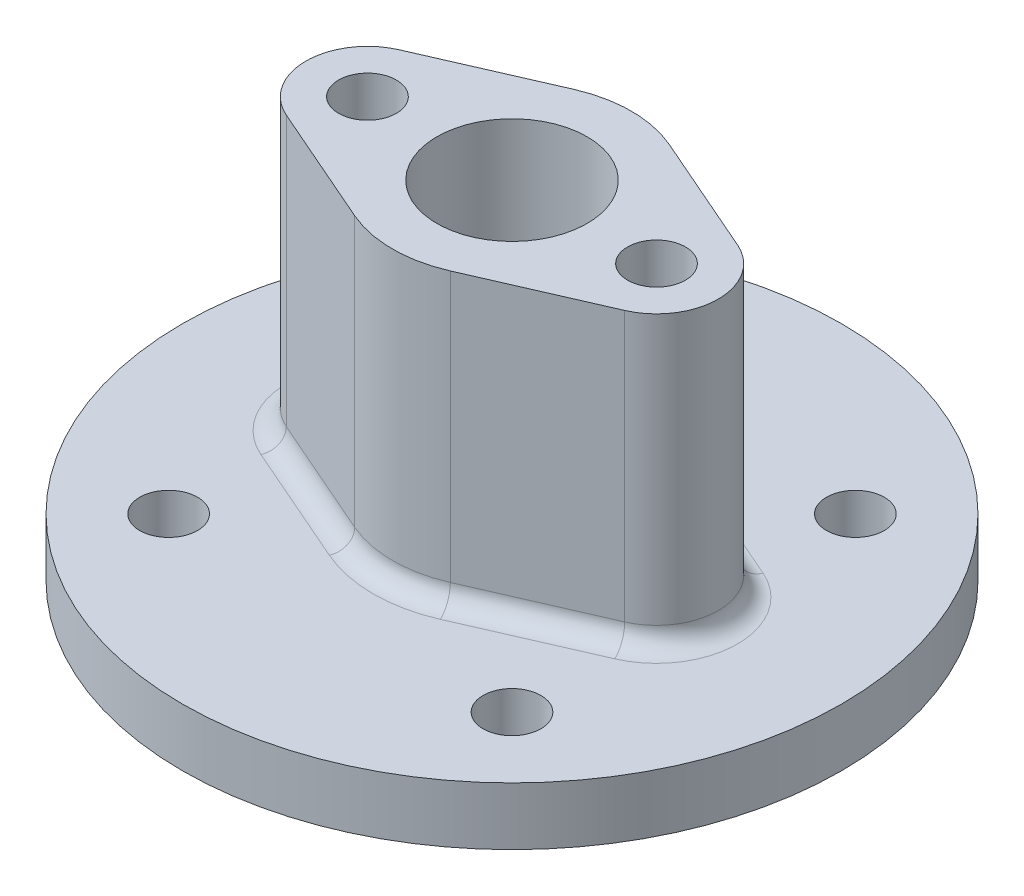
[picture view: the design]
ISO-10303-21;
HEADER;
FILE_DESCRIPTION(('STEP AP214'),'2;1');
FILE_NAME('part.step','',(''),(''),'','','');
FILE_SCHEMA(('AUTOMOTIVE_DESIGN { 1 0 10303 214 1 1 1 1 }'));
ENDSEC;
DATA;
#1=APPLICATION_CONTEXT('core data for automotive mechanical design processes');
#2=APPLICATION_PROTOCOL_DEFINITION('international standard','automotive_design',2000,#1);
#3=PRODUCT_CONTEXT('',#1,'mechanical');
#4=PRODUCT('Part','Part','',(#3));
#5=PRODUCT_RELATED_PRODUCT_CATEGORY('part','',(#4));
#6=PRODUCT_DEFINITION_FORMATION('','',#4);
#7=PRODUCT_DEFINITION_CONTEXT('part definition',#1,'design');
#8=PRODUCT_DEFINITION('design','',#6,#7);
#9=PRODUCT_DEFINITION_SHAPE('','',#8);
#10=(LENGTH_UNIT() NAMED_UNIT(*) SI_UNIT(.MILLI.,.METRE.));
#11=(NAMED_UNIT(*) PLANE_ANGLE_UNIT() SI_UNIT($,.RADIAN.));
#12=(NAMED_UNIT(*) SI_UNIT($,.STERADIAN.) SOLID_ANGLE_UNIT());
#13=UNCERTAINTY_MEASURE_WITH_UNIT(LENGTH_MEASURE(1.E-05),#10,'distance_accuracy_value','');
#14=(GEOMETRIC_REPRESENTATION_CONTEXT(3) GLOBAL_UNCERTAINTY_ASSIGNED_CONTEXT((#13)) GLOBAL_UNIT_ASSIGNED_CONTEXT((#10,
#11,#12)) REPRESENTATION_CONTEXT('',''));
#15=CARTESIAN_POINT('',(0.,0.,0.));
#16=DIRECTION('',(0.,0.,1.));
#17=DIRECTION('',(1.,0.,0.));
#18=AXIS2_PLACEMENT_3D('',#15,#16,#17);
#19=CARTESIAN_POINT('',(0.,0.,0.));
#20=DIRECTION('',(0.,-1.,0.));
#21=DIRECTION('',(0.,0.,-1.));
#22=AXIS2_PLACEMENT_3D('',#19,#20,#21);
#23=PLANE('',#22);
#24=CARTESIAN_POINT('',(0.,0.,0.));
#25=DIRECTION('',(0.,-1.,0.));
#26=DIRECTION('',(0.,0.,-1.));
#27=AXIS2_PLACEMENT_3D('',#24,#25,#26);
#28=CIRCLE('',#27,13.5);
#29=CARTESIAN_POINT('',(0.,0.,-13.5));
#30=VERTEX_POINT('',#29);
#31=EDGE_CURVE('E150',#30,#30,#28,.T.);
#32=ORIENTED_EDGE('',*,*,#31,.F.);
#33=EDGE_LOOP('',(#32));
#34=FACE_BOUND('',#33,.T.);
#35=CARTESIAN_POINT('',(0.,0.,0.));
#36=DIRECTION('',(0.,-1.,0.));
#37=DIRECTION('',(0.,0.,-1.));
#38=AXIS2_PLACEMENT_3D('',#35,#36,#37);
#39=CIRCLE('',#38,24.);
#40=CARTESIAN_POINT('',(0.,0.,-24.));
#41=VERTEX_POINT('',#40);
#42=EDGE_CURVE('E212',#41,#41,#39,.T.);
#43=ORIENTED_EDGE('',*,*,#42,.T.);
#44=EDGE_LOOP('',(#43));
#45=FACE_BOUND('',#44,.T.);
#46=ADVANCED_FACE('F32',(#34,#45),#23,.T.);
#47=CARTESIAN_POINT('',(0.,57.,0.));
#48=DIRECTION('',(0.,1.,0.));
#49=DIRECTION('',(0.,0.,1.));
#50=AXIS2_PLACEMENT_3D('',#47,#48,#49);
#51=PLANE('',#50);
#52=CARTESIAN_POINT('',(0.,57.,0.));
#53=DIRECTION('',(0.,1.,0.));
#54=DIRECTION('',(0.,0.,1.));
#55=AXIS2_PLACEMENT_3D('',#52,#53,#54);
#56=CIRCLE('',#55,36.);
#57=CARTESIAN_POINT('',(14.4,57.,32.994545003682));
#58=VERTEX_POINT('',#57);
#59=CARTESIAN_POINT('',(-14.4,57.,32.994545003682));
#60=VERTEX_POINT('',#59);
#61=EDGE_CURVE('E240',#58,#60,#56,.F.);
#62=ORIENTED_EDGE('',*,*,#61,.T.);
#63=DIRECTION('',(0.916515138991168,0.,0.4));
#64=VECTOR('',#63,1.);
#65=CARTESIAN_POINT('',(-14.4,57.,32.9945450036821));
#66=LINE('',#65,#64);
#67=CARTESIAN_POINT('',(-45.9,57.,19.2468179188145));
#68=VERTEX_POINT('',#67);
#69=EDGE_CURVE('E254',#60,#68,#66,.F.);
#70=ORIENTED_EDGE('',*,*,#69,.T.);
#71=CARTESIAN_POINT('',(-37.5,57.,0.));
#72=DIRECTION('',(0.,1.,0.));
#73=DIRECTION('',(0.,0.,1.));
#74=AXIS2_PLACEMENT_3D('',#71,#72,#73);
#75=CIRCLE('',#74,21.);
#76=CARTESIAN_POINT('',(-45.9,57.,-19.2468179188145));
#77=VERTEX_POINT('',#76);
#78=EDGE_CURVE('E252',#68,#77,#75,.F.);
#79=ORIENTED_EDGE('',*,*,#78,.T.);
#80=DIRECTION('',(-0.916515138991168,0.,0.4));
#81=VECTOR('',#80,1.);
#82=CARTESIAN_POINT('',(-14.4,57.,-32.9945450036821));
#83=LINE('',#82,#81);
#84=CARTESIAN_POINT('',(-14.4,57.,-32.994545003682));
#85=VERTEX_POINT('',#84);
#86=EDGE_CURVE('E250',#77,#85,#83,.F.);
#87=ORIENTED_EDGE('',*,*,#86,.T.);
#88=CARTESIAN_POINT('',(0.,57.,0.));
#89=DIRECTION('',(0.,1.,0.));
#90=DIRECTION('',(0.,0.,1.));
#91=AXIS2_PLACEMENT_3D('',#88,#89,#90);
#92=CIRCLE('',#91,36.);
#93=CARTESIAN_POINT('',(14.4,57.,-32.9945450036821));
#94=VERTEX_POINT('',#93);
#95=EDGE_CURVE('E248',#85,#94,#92,.F.);
#96=ORIENTED_EDGE('',*,*,#95,.T.);
#97=DIRECTION('',(-0.916515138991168,0.,-0.4));
#98=VECTOR('',#97,1.);
#99=CARTESIAN_POINT('',(14.4,57.,-32.9945450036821));
#100=LINE('',#99,#98);
#101=CARTESIAN_POINT('',(45.9,57.,-19.2468179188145));
#102=VERTEX_POINT('',#101);
#103=EDGE_CURVE('E246',#94,#102,#100,.F.);
#104=ORIENTED_EDGE('',*,*,#103,.T.);
#105=CARTESIAN_POINT('',(37.5,57.,0.));
#106=DIRECTION('',(0.,1.,0.));
#107=DIRECTION('',(0.,0.,1.));
#108=AXIS2_PLACEMENT_3D('',#105,#106,#107);
#109=CIRCLE('',#108,21.);
#110=CARTESIAN_POINT('',(45.9,57.,19.2468179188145));
#111=VERTEX_POINT('',#110);
#112=EDGE_CURVE('E244',#102,#111,#109,.F.);
#113=ORIENTED_EDGE('',*,*,#112,.T.);
#114=DIRECTION('',(0.916515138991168,0.,-0.4));
#115=VECTOR('',#114,1.);
#116=CARTESIAN_POINT('',(14.4,57.,32.994545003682));
#117=LINE('',#116,#115);
#118=EDGE_CURVE('E242',#111,#58,#117,.F.);
#119=ORIENTED_EDGE('',*,*,#118,.T.);
#120=EDGE_LOOP('',(#62,#70,#79,#87,#96,#104,#113,#119));
#121=FACE_BOUND('',#120,.T.);
#122=CARTESIAN_POINT('',(44.5477272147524,57.,44.5477272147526));
#123=DIRECTION('',(0.,1.,0.));
#124=DIRECTION('',(-1.,0.,0.));
#125=AXIS2_PLACEMENT_3D('',#122,#123,#124);
#126=CIRCLE('',#125,7.5);
#127=CARTESIAN_POINT('',(44.5477272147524,57.,52.0477272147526));
#128=VERTEX_POINT('',#127);
#129=EDGE_CURVE('E232',#128,#128,#126,.T.);
#130=ORIENTED_EDGE('',*,*,#129,.F.);
#131=EDGE_LOOP('',(#130));
#132=FACE_BOUND('',#131,.T.);
#133=CARTESIAN_POINT('',(-44.5477272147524,57.,44.5477272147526));
#134=DIRECTION('',(0.,1.,0.));
#135=DIRECTION('',(0.,0.,-1.));
#136=AXIS2_PLACEMENT_3D('',#133,#134,#135);
#137=CIRCLE('',#136,7.5);
#138=CARTESIAN_POINT('',(-44.5477272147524,57.,52.0477272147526));
#139=VERTEX_POINT('',#138);
#140=EDGE_CURVE('E296',#139,#139,#137,.T.);
#141=ORIENTED_EDGE('',*,*,#140,.F.);
#142=EDGE_LOOP('',(#141));
#143=FACE_BOUND('',#142,.T.);
#144=CARTESIAN_POINT('',(-44.5477272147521,57.,-44.5477272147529));
#145=DIRECTION('',(0.,1.,0.));
#146=DIRECTION('',(1.,0.,0.));
#147=AXIS2_PLACEMENT_3D('',#144,#145,#146);
#148=CIRCLE('',#147,7.5);
#149=CARTESIAN_POINT('',(-44.5477272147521,57.,-37.0477272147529));
#150=VERTEX_POINT('',#149);
#151=EDGE_CURVE('E290',#150,#150,#148,.T.);
#152=ORIENTED_EDGE('',*,*,#151,.F.);
#153=EDGE_LOOP('',(#152));
#154=FACE_BOUND('',#153,.T.);
#155=CARTESIAN_POINT('',(44.5477272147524,57.,-44.5477272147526));
#156=DIRECTION('',(0.,1.,0.));
#157=DIRECTION('',(0.,0.,1.));
#158=AXIS2_PLACEMENT_3D('',#155,#156,#157);
#159=CIRCLE('',#158,7.5);
#160=CARTESIAN_POINT('',(44.5477272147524,57.,-37.0477272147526));
#161=VERTEX_POINT('',#160);
#162=EDGE_CURVE('E227',#161,#161,#159,.T.);
#163=ORIENTED_EDGE('',*,*,#162,.F.);
#164=EDGE_LOOP('',(#163));
#165=FACE_BOUND('',#164,.T.);
#166=CARTESIAN_POINT('',(0.,57.,0.));
#167=DIRECTION('',(0.,-1.,0.));
#168=DIRECTION('',(0.,0.,-1.));
#169=AXIS2_PLACEMENT_3D('',#166,#167,#168);
#170=CIRCLE('',#169,85.5);
#171=CARTESIAN_POINT('',(0.,57.,-85.5));
#172=VERTEX_POINT('',#171);
#173=EDGE_CURVE('E221',#172,#172,#170,.T.);
#174=ORIENTED_EDGE('',*,*,#173,.F.);
#175=EDGE_LOOP('',(#174));
#176=FACE_BOUND('',#175,.T.);
#177=ADVANCED_FACE('F308',(#121,#132,#143,#154,#165,#176),#51,.T.);
#178=CARTESIAN_POINT('',(0.,0.,0.));
#179=DIRECTION('',(0.,-1.,0.));
#180=DIRECTION('',(0.,0.,-1.));
#181=AXIS2_PLACEMENT_3D('',#178,#179,#180);
#182=CYLINDRICAL_SURFACE('',#181,85.5);
#183=ORIENTED_EDGE('',*,*,#173,.T.);
#184=EDGE_LOOP('',(#183));
#185=FACE_BOUND('',#184,.T.);
#186=CARTESIAN_POINT('',(0.,42.,0.));
#187=DIRECTION('',(0.,-1.,0.));
#188=DIRECTION('',(0.,0.,-1.));
#189=AXIS2_PLACEMENT_3D('',#186,#187,#188);
#190=CIRCLE('',#189,85.5);
#191=CARTESIAN_POINT('',(0.,42.,-85.5));
#192=VERTEX_POINT('',#191);
#193=EDGE_CURVE('E218',#192,#192,#190,.T.);
#194=ORIENTED_EDGE('',*,*,#193,.F.);
#195=EDGE_LOOP('',(#194));
#196=FACE_BOUND('',#195,.T.);
#197=ADVANCED_FACE('F311',(#185,#196),#182,.T.);
#198=CARTESIAN_POINT('',(42.,42.,0.));
#199=DIRECTION('',(0.,-1.,0.));
#200=DIRECTION('',(0.,0.,-1.));
#201=AXIS2_PLACEMENT_3D('',#198,#199,#200);
#202=PLANE('',#201);
#203=CARTESIAN_POINT('',(44.5477272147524,42.,44.5477272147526));
#204=DIRECTION('',(0.,-1.,0.));
#205=DIRECTION('',(0.,0.,-1.));
#206=AXIS2_PLACEMENT_3D('',#203,#204,#205);
#207=CIRCLE('',#206,7.5);
#208=CARTESIAN_POINT('',(44.5477272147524,42.,52.0477272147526));
#209=VERTEX_POINT('',#208);
#210=EDGE_CURVE('E235',#209,#209,#207,.T.);
#211=ORIENTED_EDGE('',*,*,#210,.F.);
#212=EDGE_LOOP('',(#211));
#213=FACE_BOUND('',#212,.T.);
#214=CARTESIAN_POINT('',(-44.5477272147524,42.,44.5477272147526));
#215=DIRECTION('',(0.,-1.,0.));
#216=DIRECTION('',(0.,0.,-1.));
#217=AXIS2_PLACEMENT_3D('',#214,#215,#216);
#218=CIRCLE('',#217,7.5);
#219=CARTESIAN_POINT('',(-44.5477272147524,42.,52.0477272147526));
#220=VERTEX_POINT('',#219);
#221=EDGE_CURVE('E231',#220,#220,#218,.T.);
#222=ORIENTED_EDGE('',*,*,#221,.F.);
#223=EDGE_LOOP('',(#222));
#224=FACE_BOUND('',#223,.T.);
#225=CARTESIAN_POINT('',(-44.5477272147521,42.,-44.5477272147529));
#226=DIRECTION('',(0.,-1.,0.));
#227=DIRECTION('',(0.,0.,-1.));
#228=AXIS2_PLACEMENT_3D('',#225,#226,#227);
#229=CIRCLE('',#228,7.5);
#230=CARTESIAN_POINT('',(-44.5477272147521,42.,-37.0477272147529));
#231=VERTEX_POINT('',#230);
#232=EDGE_CURVE('E228',#231,#231,#229,.T.);
#233=ORIENTED_EDGE('',*,*,#232,.F.);
#234=EDGE_LOOP('',(#233));
#235=FACE_BOUND('',#234,.T.);
#236=CARTESIAN_POINT('',(44.5477272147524,42.,-44.5477272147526));
#237=DIRECTION('',(0.,-1.,0.));
#238=DIRECTION('',(0.,0.,-1.));
#239=AXIS2_PLACEMENT_3D('',#236,#237,#238);
#240=CIRCLE('',#239,7.5);
#241=CARTESIAN_POINT('',(44.5477272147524,42.,-37.0477272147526));
#242=VERTEX_POINT('',#241);
#243=EDGE_CURVE('E144',#242,#242,#240,.T.);
#244=ORIENTED_EDGE('',*,*,#243,.F.);
#245=EDGE_LOOP('',(#244));
#246=FACE_BOUND('',#245,.T.);
#247=ORIENTED_EDGE('',*,*,#193,.T.);
#248=EDGE_LOOP('',(#247));
#249=FACE_BOUND('',#248,.T.);
#250=CARTESIAN_POINT('',(0.,42.,0.));
#251=DIRECTION('',(0.,-1.,0.));
#252=DIRECTION('',(0.,0.,-1.));
#253=AXIS2_PLACEMENT_3D('',#250,#251,#252);
#254=CIRCLE('',#253,42.);
#255=CARTESIAN_POINT('',(0.,42.,-42.));
#256=VERTEX_POINT('',#255);
#257=EDGE_CURVE('E215',#256,#256,#254,.T.);
#258=ORIENTED_EDGE('',*,*,#257,.F.);
#259=EDGE_LOOP('',(#258));
#260=FACE_BOUND('',#259,.T.);
#261=ADVANCED_FACE('F318',(#213,#224,#235,#246,#249,#260),#202,.T.);
#262=CARTESIAN_POINT('',(0.,0.,0.));
#263=DIRECTION('',(0.,1.,0.));
#264=DIRECTION('',(0.,0.,1.));
#265=AXIS2_PLACEMENT_3D('',#262,#263,#264);
#266=CONICAL_SURFACE('',#265,24.,0.404891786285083);
#267=ORIENTED_EDGE('',*,*,#257,.T.);
#268=EDGE_LOOP('',(#267));
#269=FACE_BOUND('',#268,.T.);
#270=ORIENTED_EDGE('',*,*,#42,.F.);
#271=EDGE_LOOP('',(#270));
#272=FACE_BOUND('',#271,.T.);
#273=ADVANCED_FACE('F324',(#269,#272),#266,.T.);
#274=CARTESIAN_POINT('',(-37.5,132.,0.));
#275=DIRECTION('',(0.,-1.,0.));
#276=DIRECTION('',(0.,0.,-1.));
#277=AXIS2_PLACEMENT_3D('',#274,#275,#276);
#278=CYLINDRICAL_SURFACE('',#277,16.);
#279=DIRECTION('',(0.,-1.,0.));
#280=VECTOR('',#279,1.);
#281=CARTESIAN_POINT('',(-43.9,132.,-14.6642422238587));
#282=LINE('',#281,#280);
#283=CARTESIAN_POINT('',(-43.9,132.,-14.6642422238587));
#284=VERTEX_POINT('',#283);
#285=CARTESIAN_POINT('',(-43.9,62.,-14.6642422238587));
#286=VERTEX_POINT('',#285);
#287=EDGE_CURVE('E191',#284,#286,#282,.T.);
#288=ORIENTED_EDGE('',*,*,#287,.T.);
#289=CARTESIAN_POINT('',(-37.5,62.,0.));
#290=DIRECTION('',(0.,1.,0.));
#291=DIRECTION('',(0.,0.,1.));
#292=AXIS2_PLACEMENT_3D('',#289,#290,#291);
#293=CIRCLE('',#292,16.);
#294=CARTESIAN_POINT('',(-43.9,62.,14.6642422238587));
#295=VERTEX_POINT('',#294);
#296=EDGE_CURVE('E257',#286,#295,#293,.T.);
#297=ORIENTED_EDGE('',*,*,#296,.T.);
#298=DIRECTION('',(0.,-1.,0.));
#299=VECTOR('',#298,1.);
#300=CARTESIAN_POINT('',(-43.9,132.,14.6642422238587));
#301=LINE('',#300,#299);
#302=CARTESIAN_POINT('',(-43.9,132.,14.6642422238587));
#303=VERTEX_POINT('',#302);
#304=EDGE_CURVE('E209',#303,#295,#301,.T.);
#305=ORIENTED_EDGE('',*,*,#304,.F.);
#306=CARTESIAN_POINT('',(-37.5,132.,0.));
#307=DIRECTION('',(0.,1.,0.));
#308=DIRECTION('',(0.,0.,1.));
#309=AXIS2_PLACEMENT_3D('',#306,#307,#308);
#310=CIRCLE('',#309,16.);
#311=EDGE_CURVE('E174',#284,#303,#310,.T.);
#312=ORIENTED_EDGE('',*,*,#311,.F.);
#313=EDGE_LOOP('',(#288,#297,#305,#312));
#314=FACE_BOUND('',#313,.T.);
#315=ADVANCED_FACE('F331',(#314),#278,.T.);
#316=CARTESIAN_POINT('',(-43.9,132.,14.6642422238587));
#317=DIRECTION('',(0.4,0.,-0.916515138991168));
#318=DIRECTION('',(-0.916515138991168,0.,-0.4));
#319=AXIS2_PLACEMENT_3D('',#316,#317,#318);
#320=PLANE('',#319);
#321=ORIENTED_EDGE('',*,*,#304,.T.);
#322=DIRECTION('',(0.916515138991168,0.,0.4));
#323=VECTOR('',#322,1.);
#324=CARTESIAN_POINT('',(-43.9,62.,14.6642422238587));
#325=LINE('',#324,#323);
#326=CARTESIAN_POINT('',(-12.4,62.,28.4119693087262));
#327=VERTEX_POINT('',#326);
#328=EDGE_CURVE('E224',#295,#327,#325,.T.);
#329=ORIENTED_EDGE('',*,*,#328,.T.);
#330=DIRECTION('',(0.,-1.,0.));
#331=VECTOR('',#330,1.);
#332=CARTESIAN_POINT('',(-12.4,132.,28.4119693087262));
#333=LINE('',#332,#331);
#334=CARTESIAN_POINT('',(-12.4,132.,28.4119693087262));
#335=VERTEX_POINT('',#334);
#336=EDGE_CURVE('E207',#335,#327,#333,.T.);
#337=ORIENTED_EDGE('',*,*,#336,.F.);
#338=DIRECTION('',(0.916515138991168,0.,0.4));
#339=VECTOR('',#338,1.);
#340=CARTESIAN_POINT('',(-43.9,132.,14.6642422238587));
#341=LINE('',#340,#339);
#342=EDGE_CURVE('E177',#303,#335,#341,.T.);
#343=ORIENTED_EDGE('',*,*,#342,.F.);
#344=EDGE_LOOP('',(#321,#329,#337,#343));
#345=FACE_BOUND('',#344,.T.);
#346=ADVANCED_FACE('F417',(#345),#320,.F.);
#347=CARTESIAN_POINT('',(0.,132.,0.));
#348=DIRECTION('',(0.,-1.,0.));
#349=DIRECTION('',(0.,0.,-1.));
#350=AXIS2_PLACEMENT_3D('',#347,#348,#349);
#351=CYLINDRICAL_SURFACE('',#350,31.);
#352=ORIENTED_EDGE('',*,*,#336,.T.);
#353=CARTESIAN_POINT('',(0.,62.,0.));
#354=DIRECTION('',(0.,1.,0.));
#355=DIRECTION('',(0.,0.,1.));
#356=AXIS2_PLACEMENT_3D('',#353,#354,#355);
#357=CIRCLE('',#356,31.);
#358=CARTESIAN_POINT('',(12.4,62.,28.4119693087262));
#359=VERTEX_POINT('',#358);
#360=EDGE_CURVE('E11',#327,#359,#357,.T.);
#361=ORIENTED_EDGE('',*,*,#360,.T.);
#362=DIRECTION('',(0.,-1.,0.));
#363=VECTOR('',#362,1.);
#364=CARTESIAN_POINT('',(12.4,132.,28.4119693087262));
#365=LINE('',#364,#363);
#366=CARTESIAN_POINT('',(12.4,132.,28.4119693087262));
#367=VERTEX_POINT('',#366);
#368=EDGE_CURVE('E205',#367,#359,#365,.T.);
#369=ORIENTED_EDGE('',*,*,#368,.F.);
#370=CARTESIAN_POINT('',(0.,132.,0.));
#371=DIRECTION('',(0.,1.,0.));
#372=DIRECTION('',(0.,0.,1.));
#373=AXIS2_PLACEMENT_3D('',#370,#371,#372);
#374=CIRCLE('',#373,31.);
#375=EDGE_CURVE('E179',#335,#367,#374,.T.);
#376=ORIENTED_EDGE('',*,*,#375,.F.);
#377=EDGE_LOOP('',(#352,#361,#369,#376));
#378=FACE_BOUND('',#377,.T.);
#379=ADVANCED_FACE('F419',(#378),#351,.T.);
#380=CARTESIAN_POINT('',(12.4,132.,28.4119693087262));
#381=DIRECTION('',(-0.4,0.,-0.916515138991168));
#382=DIRECTION('',(-0.916515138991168,0.,0.4));
#383=AXIS2_PLACEMENT_3D('',#380,#381,#382);
#384=PLANE('',#383);
#385=ORIENTED_EDGE('',*,*,#368,.T.);
#386=DIRECTION('',(0.916515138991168,0.,-0.4));
#387=VECTOR('',#386,1.);
#388=CARTESIAN_POINT('',(12.4,62.,28.4119693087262));
#389=LINE('',#388,#387);
#390=CARTESIAN_POINT('',(43.9,62.,14.6642422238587));
#391=VERTEX_POINT('',#390);
#392=EDGE_CURVE('E41',#359,#391,#389,.T.);
#393=ORIENTED_EDGE('',*,*,#392,.T.);
#394=DIRECTION('',(0.,-1.,0.));
#395=VECTOR('',#394,1.);
#396=CARTESIAN_POINT('',(43.9,132.,14.6642422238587));
#397=LINE('',#396,#395);
#398=CARTESIAN_POINT('',(43.9,132.,14.6642422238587));
#399=VERTEX_POINT('',#398);
#400=EDGE_CURVE('E203',#399,#391,#397,.T.);
#401=ORIENTED_EDGE('',*,*,#400,.F.);
#402=DIRECTION('',(0.916515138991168,0.,-0.4));
#403=VECTOR('',#402,1.);
#404=CARTESIAN_POINT('',(12.4,132.,28.4119693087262));
#405=LINE('',#404,#403);
#406=EDGE_CURVE('E181',#367,#399,#405,.T.);
#407=ORIENTED_EDGE('',*,*,#406,.F.);
#408=EDGE_LOOP('',(#385,#393,#401,#407));
#409=FACE_BOUND('',#408,.T.);
#410=ADVANCED_FACE('F421',(#409),#384,.F.);
#411=CARTESIAN_POINT('',(37.5,132.,0.));
#412=DIRECTION('',(0.,-1.,0.));
#413=DIRECTION('',(0.,0.,-1.));
#414=AXIS2_PLACEMENT_3D('',#411,#412,#413);
#415=CYLINDRICAL_SURFACE('',#414,16.);
#416=ORIENTED_EDGE('',*,*,#400,.T.);
#417=CARTESIAN_POINT('',(37.5,62.,0.));
#418=DIRECTION('',(0.,1.,0.));
#419=DIRECTION('',(0.,0.,1.));
#420=AXIS2_PLACEMENT_3D('',#417,#418,#419);
#421=CIRCLE('',#420,16.);
#422=CARTESIAN_POINT('',(43.9,62.,-14.6642422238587));
#423=VERTEX_POINT('',#422);
#424=EDGE_CURVE('E265',#391,#423,#421,.T.);
#425=ORIENTED_EDGE('',*,*,#424,.T.);
#426=DIRECTION('',(0.,-1.,0.));
#427=VECTOR('',#426,1.);
#428=CARTESIAN_POINT('',(43.9,132.,-14.6642422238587));
#429=LINE('',#428,#427);
#430=CARTESIAN_POINT('',(43.9,132.,-14.6642422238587));
#431=VERTEX_POINT('',#430);
#432=EDGE_CURVE('E200',#431,#423,#429,.T.);
#433=ORIENTED_EDGE('',*,*,#432,.F.);
#434=CARTESIAN_POINT('',(37.5,132.,0.));
#435=DIRECTION('',(0.,1.,0.));
#436=DIRECTION('',(0.,0.,1.));
#437=AXIS2_PLACEMENT_3D('',#434,#435,#436);
#438=CIRCLE('',#437,16.);
#439=EDGE_CURVE('E183',#399,#431,#438,.T.);
#440=ORIENTED_EDGE('',*,*,#439,.F.);
#441=EDGE_LOOP('',(#416,#425,#433,#440));
#442=FACE_BOUND('',#441,.T.);
#443=ADVANCED_FACE('F409',(#442),#415,.T.);
#444=CARTESIAN_POINT('',(12.4,132.,-28.4119693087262));
#445=DIRECTION('',(-0.4,0.,0.916515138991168));
#446=DIRECTION('',(0.916515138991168,0.,0.4));
#447=AXIS2_PLACEMENT_3D('',#444,#445,#446);
#448=PLANE('',#447);
#449=ORIENTED_EDGE('',*,*,#432,.T.);
#450=DIRECTION('',(-0.916515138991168,0.,-0.4));
#451=VECTOR('',#450,1.);
#452=CARTESIAN_POINT('',(12.4,62.,-28.4119693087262));
#453=LINE('',#452,#451);
#454=CARTESIAN_POINT('',(12.4,62.,-28.4119693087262));
#455=VERTEX_POINT('',#454);
#456=EDGE_CURVE('E263',#423,#455,#453,.T.);
#457=ORIENTED_EDGE('',*,*,#456,.T.);
#458=DIRECTION('',(0.,-1.,0.));
#459=VECTOR('',#458,1.);
#460=CARTESIAN_POINT('',(12.4,132.,-28.4119693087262));
#461=LINE('',#460,#459);
#462=CARTESIAN_POINT('',(12.4,132.,-28.4119693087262));
#463=VERTEX_POINT('',#462);
#464=EDGE_CURVE('E197',#463,#455,#461,.T.);
#465=ORIENTED_EDGE('',*,*,#464,.F.);
#466=DIRECTION('',(-0.916515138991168,0.,-0.4));
#467=VECTOR('',#466,1.);
#468=CARTESIAN_POINT('',(12.4,132.,-28.4119693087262));
#469=LINE('',#468,#467);
#470=EDGE_CURVE('E185',#431,#463,#469,.T.);
#471=ORIENTED_EDGE('',*,*,#470,.F.);
#472=EDGE_LOOP('',(#449,#457,#465,#471));
#473=FACE_BOUND('',#472,.T.);
#474=ADVANCED_FACE('F405',(#473),#448,.F.);
#475=CARTESIAN_POINT('',(0.,132.,0.));
#476=DIRECTION('',(0.,-1.,0.));
#477=DIRECTION('',(0.,0.,-1.));
#478=AXIS2_PLACEMENT_3D('',#475,#476,#477);
#479=CYLINDRICAL_SURFACE('',#478,31.);
#480=ORIENTED_EDGE('',*,*,#464,.T.);
#481=CARTESIAN_POINT('',(0.,62.,0.));
#482=DIRECTION('',(0.,1.,0.));
#483=DIRECTION('',(0.,0.,1.));
#484=AXIS2_PLACEMENT_3D('',#481,#482,#483);
#485=CIRCLE('',#484,31.);
#486=CARTESIAN_POINT('',(-12.4,62.,-28.4119693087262));
#487=VERTEX_POINT('',#486);
#488=EDGE_CURVE('E261',#455,#487,#485,.T.);
#489=ORIENTED_EDGE('',*,*,#488,.T.);
#490=DIRECTION('',(0.,-1.,0.));
#491=VECTOR('',#490,1.);
#492=CARTESIAN_POINT('',(-12.4,132.,-28.4119693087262));
#493=LINE('',#492,#491);
#494=CARTESIAN_POINT('',(-12.4,132.,-28.4119693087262));
#495=VERTEX_POINT('',#494);
#496=EDGE_CURVE('E194',#495,#487,#493,.T.);
#497=ORIENTED_EDGE('',*,*,#496,.F.);
#498=CARTESIAN_POINT('',(0.,132.,0.));
#499=DIRECTION('',(0.,1.,0.));
#500=DIRECTION('',(0.,0.,1.));
#501=AXIS2_PLACEMENT_3D('',#498,#499,#500);
#502=CIRCLE('',#501,31.);
#503=EDGE_CURVE('E187',#463,#495,#502,.T.);
#504=ORIENTED_EDGE('',*,*,#503,.F.);
#505=EDGE_LOOP('',(#480,#489,#497,#504));
#506=FACE_BOUND('',#505,.T.);
#507=ADVANCED_FACE('F403',(#506),#479,.T.);
#508=CARTESIAN_POINT('',(-43.9,132.,-14.6642422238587));
#509=DIRECTION('',(0.4,0.,0.916515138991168));
#510=DIRECTION('',(0.916515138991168,0.,-0.4));
#511=AXIS2_PLACEMENT_3D('',#508,#509,#510);
#512=PLANE('',#511);
#513=ORIENTED_EDGE('',*,*,#496,.T.);
#514=DIRECTION('',(-0.916515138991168,0.,0.4));
#515=VECTOR('',#514,1.);
#516=CARTESIAN_POINT('',(-43.9,62.,-14.6642422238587));
#517=LINE('',#516,#515);
#518=EDGE_CURVE('E259',#487,#286,#517,.T.);
#519=ORIENTED_EDGE('',*,*,#518,.T.);
#520=ORIENTED_EDGE('',*,*,#287,.F.);
#521=DIRECTION('',(-0.916515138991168,0.,0.4));
#522=VECTOR('',#521,1.);
#523=CARTESIAN_POINT('',(-43.9,132.,-14.6642422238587));
#524=LINE('',#523,#522);
#525=EDGE_CURVE('E189',#495,#284,#524,.T.);
#526=ORIENTED_EDGE('',*,*,#525,.F.);
#527=EDGE_LOOP('',(#513,#519,#520,#526));
#528=FACE_BOUND('',#527,.T.);
#529=ADVANCED_FACE('F390',(#528),#512,.F.);
#530=CARTESIAN_POINT('',(-37.5,132.,0.));
#531=DIRECTION('',(0.,1.,0.));
#532=DIRECTION('',(0.,0.,1.));
#533=AXIS2_PLACEMENT_3D('',#530,#531,#532);
#534=PLANE('',#533);
#535=CARTESIAN_POINT('',(37.5,132.,0.));
#536=DIRECTION('',(0.,1.,0.));
#537=DIRECTION('',(0.,0.,1.));
#538=AXIS2_PLACEMENT_3D('',#535,#536,#537);
#539=CIRCLE('',#538,7.49999999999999);
#540=CARTESIAN_POINT('',(37.5,132.,7.49999999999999));
#541=VERTEX_POINT('',#540);
#542=EDGE_CURVE('E138',#541,#541,#539,.T.);
#543=ORIENTED_EDGE('',*,*,#542,.F.);
#544=EDGE_LOOP('',(#543));
#545=FACE_BOUND('',#544,.T.);
#546=CARTESIAN_POINT('',(-37.5,132.,0.));
#547=DIRECTION('',(0.,1.,0.));
#548=DIRECTION('',(0.,0.,1.));
#549=AXIS2_PLACEMENT_3D('',#546,#547,#548);
#550=CIRCLE('',#549,7.49999999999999);
#551=CARTESIAN_POINT('',(-37.5,132.,7.49999999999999));
#552=VERTEX_POINT('',#551);
#553=EDGE_CURVE('E137',#552,#552,#550,.T.);
#554=ORIENTED_EDGE('',*,*,#553,.F.);
#555=EDGE_LOOP('',(#554));
#556=FACE_BOUND('',#555,.T.);
#557=CARTESIAN_POINT('',(0.,132.,0.));
#558=DIRECTION('',(0.,-1.,0.));
#559=DIRECTION('',(0.,0.,-1.));
#560=AXIS2_PLACEMENT_3D('',#557,#558,#559);
#561=CIRCLE('',#560,19.5);
#562=CARTESIAN_POINT('',(0.,132.,-19.5));
#563=VERTEX_POINT('',#562);
#564=EDGE_CURVE('E171',#563,#563,#561,.T.);
#565=ORIENTED_EDGE('',*,*,#564,.T.);
#566=EDGE_LOOP('',(#565));
#567=FACE_BOUND('',#566,.T.);
#568=ORIENTED_EDGE('',*,*,#311,.T.);
#569=ORIENTED_EDGE('',*,*,#342,.T.);
#570=ORIENTED_EDGE('',*,*,#375,.T.);
#571=ORIENTED_EDGE('',*,*,#406,.T.);
#572=ORIENTED_EDGE('',*,*,#439,.T.);
#573=ORIENTED_EDGE('',*,*,#470,.T.);
#574=ORIENTED_EDGE('',*,*,#503,.T.);
#575=ORIENTED_EDGE('',*,*,#525,.T.);
#576=EDGE_LOOP('',(#568,#569,#570,#571,#572,#573,#574,#575));
#577=FACE_BOUND('',#576,.T.);
#578=ADVANCED_FACE('F397',(#545,#556,#567,#577),#534,.T.);
#579=CARTESIAN_POINT('',(0.,0.,0.));
#580=DIRECTION('',(0.,-1.,0.));
#581=DIRECTION('',(0.,0.,-1.));
#582=AXIS2_PLACEMENT_3D('',#579,#580,#581);
#583=CYLINDRICAL_SURFACE('',#582,19.5);
#584=ORIENTED_EDGE('',*,*,#564,.F.);
#585=EDGE_LOOP('',(#584));
#586=FACE_BOUND('',#585,.T.);
#587=CARTESIAN_POINT('',(0.,102.,0.));
#588=DIRECTION('',(0.,-1.,0.));
#589=DIRECTION('',(0.,0.,-1.));
#590=AXIS2_PLACEMENT_3D('',#587,#588,#589);
#591=CIRCLE('',#590,19.5);
#592=CARTESIAN_POINT('',(0.,102.,-19.5));
#593=VERTEX_POINT('',#592);
#594=EDGE_CURVE('E168',#593,#593,#591,.T.);
#595=ORIENTED_EDGE('',*,*,#594,.T.);
#596=EDGE_LOOP('',(#595));
#597=FACE_BOUND('',#596,.T.);
#598=ADVANCED_FACE('F644',(#586,#597),#583,.F.);
#599=CARTESIAN_POINT('',(19.5,102.,0.));
#600=DIRECTION('',(0.,-1.,0.));
#601=DIRECTION('',(0.,0.,-1.));
#602=AXIS2_PLACEMENT_3D('',#599,#600,#601);
#603=PLANE('',#602);
#604=ORIENTED_EDGE('',*,*,#594,.F.);
#605=EDGE_LOOP('',(#604));
#606=FACE_BOUND('',#605,.T.);
#607=CARTESIAN_POINT('',(0.,102.,0.));
#608=DIRECTION('',(0.,-1.,0.));
#609=DIRECTION('',(0.,0.,-1.));
#610=AXIS2_PLACEMENT_3D('',#607,#608,#609);
#611=CIRCLE('',#610,10.5);
#612=CARTESIAN_POINT('',(0.,102.,-10.5));
#613=VERTEX_POINT('',#612);
#614=EDGE_CURVE('E165',#613,#613,#611,.T.);
#615=ORIENTED_EDGE('',*,*,#614,.T.);
#616=EDGE_LOOP('',(#615));
#617=FACE_BOUND('',#616,.T.);
#618=ADVANCED_FACE('F635',(#606,#617),#603,.F.);
#619=CARTESIAN_POINT('',(0.,0.,0.));
#620=DIRECTION('',(0.,-1.,0.));
#621=DIRECTION('',(0.,0.,-1.));
#622=AXIS2_PLACEMENT_3D('',#619,#620,#621);
#623=CYLINDRICAL_SURFACE('',#622,10.5);
#624=ORIENTED_EDGE('',*,*,#614,.F.);
#625=EDGE_LOOP('',(#624));
#626=FACE_BOUND('',#625,.T.);
#627=CARTESIAN_POINT('',(0.,90.,0.));
#628=DIRECTION('',(0.,-1.,0.));
#629=DIRECTION('',(0.,0.,-1.));
#630=AXIS2_PLACEMENT_3D('',#627,#628,#629);
#631=CIRCLE('',#630,10.5);
#632=CARTESIAN_POINT('',(0.,90.,-10.5));
#633=VERTEX_POINT('',#632);
#634=EDGE_CURVE('E162',#633,#633,#631,.T.);
#635=ORIENTED_EDGE('',*,*,#634,.T.);
#636=EDGE_LOOP('',(#635));
#637=FACE_BOUND('',#636,.T.);
#638=ADVANCED_FACE('F626',(#626,#637),#623,.F.);
#639=CARTESIAN_POINT('',(10.5,90.,0.));
#640=DIRECTION('',(0.,1.,0.));
#641=DIRECTION('',(0.,0.,1.));
#642=AXIS2_PLACEMENT_3D('',#639,#640,#641);
#643=PLANE('',#642);
#644=ORIENTED_EDGE('',*,*,#634,.F.);
#645=EDGE_LOOP('',(#644));
#646=FACE_BOUND('',#645,.T.);
#647=CARTESIAN_POINT('',(0.,90.,0.));
#648=DIRECTION('',(0.,-1.,0.));
#649=DIRECTION('',(0.,0.,-1.));
#650=AXIS2_PLACEMENT_3D('',#647,#648,#649);
#651=CIRCLE('',#650,19.5);
#652=CARTESIAN_POINT('',(0.,90.,-19.5));
#653=VERTEX_POINT('',#652);
#654=EDGE_CURVE('E159',#653,#653,#651,.T.);
#655=ORIENTED_EDGE('',*,*,#654,.T.);
#656=EDGE_LOOP('',(#655));
#657=FACE_BOUND('',#656,.T.);
#658=ADVANCED_FACE('F617',(#646,#657),#643,.F.);
#659=CARTESIAN_POINT('',(0.,0.,0.));
#660=DIRECTION('',(0.,-1.,0.));
#661=DIRECTION('',(0.,0.,-1.));
#662=AXIS2_PLACEMENT_3D('',#659,#660,#661);
#663=CYLINDRICAL_SURFACE('',#662,19.5);
#664=ORIENTED_EDGE('',*,*,#654,.F.);
#665=EDGE_LOOP('',(#664));
#666=FACE_BOUND('',#665,.T.);
#667=CARTESIAN_POINT('',(0.,66.,0.));
#668=DIRECTION('',(0.,-1.,0.));
#669=DIRECTION('',(0.,0.,-1.));
#670=AXIS2_PLACEMENT_3D('',#667,#668,#669);
#671=CIRCLE('',#670,19.5);
#672=CARTESIAN_POINT('',(0.,66.,-19.5));
#673=VERTEX_POINT('',#672);
#674=EDGE_CURVE('E156',#673,#673,#671,.T.);
#675=ORIENTED_EDGE('',*,*,#674,.T.);
#676=EDGE_LOOP('',(#675));
#677=FACE_BOUND('',#676,.T.);
#678=ADVANCED_FACE('F608',(#666,#677),#663,.F.);
#679=CARTESIAN_POINT('',(19.5,66.,0.));
#680=DIRECTION('',(0.,-1.,0.));
#681=DIRECTION('',(0.,0.,-1.));
#682=AXIS2_PLACEMENT_3D('',#679,#680,#681);
#683=PLANE('',#682);
#684=ORIENTED_EDGE('',*,*,#674,.F.);
#685=EDGE_LOOP('',(#684));
#686=FACE_BOUND('',#685,.T.);
#687=CARTESIAN_POINT('',(0.,66.,0.));
#688=DIRECTION('',(0.,-1.,0.));
#689=DIRECTION('',(0.,0.,-1.));
#690=AXIS2_PLACEMENT_3D('',#687,#688,#689);
#691=CIRCLE('',#690,13.5);
#692=CARTESIAN_POINT('',(0.,66.,-13.5));
#693=VERTEX_POINT('',#692);
#694=EDGE_CURVE('E153',#693,#693,#691,.T.);
#695=ORIENTED_EDGE('',*,*,#694,.T.);
#696=EDGE_LOOP('',(#695));
#697=FACE_BOUND('',#696,.T.);
#698=ADVANCED_FACE('F599',(#686,#697),#683,.F.);
#699=CARTESIAN_POINT('',(0.,0.,0.));
#700=DIRECTION('',(0.,-1.,0.));
#701=DIRECTION('',(0.,0.,-1.));
#702=AXIS2_PLACEMENT_3D('',#699,#700,#701);
#703=CYLINDRICAL_SURFACE('',#702,13.5);
#704=ORIENTED_EDGE('',*,*,#694,.F.);
#705=EDGE_LOOP('',(#704));
#706=FACE_BOUND('',#705,.T.);
#707=ORIENTED_EDGE('',*,*,#31,.T.);
#708=EDGE_LOOP('',(#707));
#709=FACE_BOUND('',#708,.T.);
#710=ADVANCED_FACE('F590',(#706,#709),#703,.F.);
#711=CARTESIAN_POINT('',(-37.5,107.,0.));
#712=DIRECTION('',(0.,1.,0.));
#713=DIRECTION('',(0.,0.,1.));
#714=AXIS2_PLACEMENT_3D('',#711,#712,#713);
#715=CONICAL_SURFACE('',#714,7.5,1.02974425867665);
#716=CARTESIAN_POINT('',(-37.5,102.493545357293,0.));
#717=VERTEX_POINT('',#716);
#718=VERTEX_LOOP('',#717);
#719=FACE_BOUND('',#718,.T.);
#720=CARTESIAN_POINT('',(-37.5,107.,0.));
#721=DIRECTION('',(0.,1.,0.));
#722=DIRECTION('',(0.,0.,1.));
#723=AXIS2_PLACEMENT_3D('',#720,#721,#722);
#724=CIRCLE('',#723,7.5);
#725=CARTESIAN_POINT('',(-37.5,107.,7.5));
#726=VERTEX_POINT('',#725);
#727=EDGE_CURVE('E141',#726,#726,#724,.T.);
#728=ORIENTED_EDGE('',*,*,#727,.T.);
#729=EDGE_LOOP('',(#728));
#730=FACE_BOUND('',#729,.T.);
#731=ADVANCED_FACE('F581',(#719,#730),#715,.F.);
#732=CARTESIAN_POINT('',(-37.5,132.,0.));
#733=DIRECTION('',(0.,1.,0.));
#734=DIRECTION('',(0.,0.,1.));
#735=AXIS2_PLACEMENT_3D('',#732,#733,#734);
#736=CYLINDRICAL_SURFACE('',#735,7.49999999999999);
#737=ORIENTED_EDGE('',*,*,#727,.F.);
#738=EDGE_LOOP('',(#737));
#739=FACE_BOUND('',#738,.T.);
#740=ORIENTED_EDGE('',*,*,#553,.T.);
#741=EDGE_LOOP('',(#740));
#742=FACE_BOUND('',#741,.T.);
#743=ADVANCED_FACE('F131',(#739,#742),#736,.F.);
#744=CARTESIAN_POINT('',(37.5,107.,0.));
#745=DIRECTION('',(0.,1.,0.));
#746=DIRECTION('',(0.,0.,1.));
#747=AXIS2_PLACEMENT_3D('',#744,#745,#746);
#748=CONICAL_SURFACE('',#747,7.5,1.02974425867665);
#749=CARTESIAN_POINT('',(37.5,102.493545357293,0.));
#750=VERTEX_POINT('',#749);
#751=VERTEX_LOOP('',#750);
#752=FACE_BOUND('',#751,.T.);
#753=CARTESIAN_POINT('',(37.5,107.,0.));
#754=DIRECTION('',(0.,1.,0.));
#755=DIRECTION('',(0.,0.,1.));
#756=AXIS2_PLACEMENT_3D('',#753,#754,#755);
#757=CIRCLE('',#756,7.5);
#758=CARTESIAN_POINT('',(37.5,107.,7.5));
#759=VERTEX_POINT('',#758);
#760=EDGE_CURVE('E135',#759,#759,#757,.T.);
#761=ORIENTED_EDGE('',*,*,#760,.T.);
#762=EDGE_LOOP('',(#761));
#763=FACE_BOUND('',#762,.T.);
#764=ADVANCED_FACE('F127',(#752,#763),#748,.F.);
#765=CARTESIAN_POINT('',(37.5,132.,0.));
#766=DIRECTION('',(0.,1.,0.));
#767=DIRECTION('',(0.,0.,1.));
#768=AXIS2_PLACEMENT_3D('',#765,#766,#767);
#769=CYLINDRICAL_SURFACE('',#768,7.49999999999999);
#770=ORIENTED_EDGE('',*,*,#760,.F.);
#771=EDGE_LOOP('',(#770));
#772=FACE_BOUND('',#771,.T.);
#773=ORIENTED_EDGE('',*,*,#542,.T.);
#774=EDGE_LOOP('',(#773));
#775=FACE_BOUND('',#774,.T.);
#776=ADVANCED_FACE('F130',(#772,#775),#769,.F.);
#777=CARTESIAN_POINT('',(44.5477272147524,0.,-44.5477272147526));
#778=DIRECTION('',(0.,1.,0.));
#779=DIRECTION('',(0.,0.,1.));
#780=AXIS2_PLACEMENT_3D('',#777,#778,#779);
#781=CYLINDRICAL_SURFACE('',#780,7.5);
#782=CARTESIAN_POINT('',(44.5477272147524,42.,-37.0477272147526));
#783=CARTESIAN_POINT('',(44.5477272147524,42.15625,-37.0477272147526));
#784=CARTESIAN_POINT('',(44.5477272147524,42.3125,-37.0477272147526));
#785=CARTESIAN_POINT('',(44.5477272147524,42.625,-37.0477272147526));
#786=CARTESIAN_POINT('',(44.5477272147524,42.78125,-37.0477272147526));
#787=CARTESIAN_POINT('',(44.5477272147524,43.09375,-37.0477272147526));
#788=CARTESIAN_POINT('',(44.5477272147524,43.25,-37.0477272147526));
#789=CARTESIAN_POINT('',(44.5477272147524,43.5625,-37.0477272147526));
#790=CARTESIAN_POINT('',(44.5477272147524,43.71875,-37.0477272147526));
#791=CARTESIAN_POINT('',(44.5477272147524,44.03125,-37.0477272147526));
#792=CARTESIAN_POINT('',(44.5477272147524,44.1875,-37.0477272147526));
#793=CARTESIAN_POINT('',(44.5477272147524,44.5,-37.0477272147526));
#794=CARTESIAN_POINT('',(44.5477272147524,44.65625,-37.0477272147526));
#795=CARTESIAN_POINT('',(44.5477272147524,44.96875,-37.0477272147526));
#796=CARTESIAN_POINT('',(44.5477272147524,45.125,-37.0477272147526));
#797=CARTESIAN_POINT('',(44.5477272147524,45.4375,-37.0477272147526));
#798=CARTESIAN_POINT('',(44.5477272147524,45.59375,-37.0477272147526));
#799=CARTESIAN_POINT('',(44.5477272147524,45.90625,-37.0477272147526));
#800=CARTESIAN_POINT('',(44.5477272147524,46.0625,-37.0477272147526));
#801=CARTESIAN_POINT('',(44.5477272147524,46.375,-37.0477272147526));
#802=CARTESIAN_POINT('',(44.5477272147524,46.53125,-37.0477272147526));
#803=CARTESIAN_POINT('',(44.5477272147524,46.84375,-37.0477272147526));
#804=CARTESIAN_POINT('',(44.5477272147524,47.,-37.0477272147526));
#805=CARTESIAN_POINT('',(44.5477272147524,47.3125,-37.0477272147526));
#806=CARTESIAN_POINT('',(44.5477272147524,47.46875,-37.0477272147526));
#807=CARTESIAN_POINT('',(44.5477272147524,47.78125,-37.0477272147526));
#808=CARTESIAN_POINT('',(44.5477272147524,47.9375,-37.0477272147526));
#809=CARTESIAN_POINT('',(44.5477272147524,48.25,-37.0477272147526));
#810=CARTESIAN_POINT('',(44.5477272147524,48.40625,-37.0477272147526));
#811=CARTESIAN_POINT('',(44.5477272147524,48.71875,-37.0477272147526));
#812=CARTESIAN_POINT('',(44.5477272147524,48.875,-37.0477272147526));
#813=CARTESIAN_POINT('',(44.5477272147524,49.1875,-37.0477272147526));
#814=CARTESIAN_POINT('',(44.5477272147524,49.34375,-37.0477272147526));
#815=CARTESIAN_POINT('',(44.5477272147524,49.65625,-37.0477272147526));
#816=CARTESIAN_POINT('',(44.5477272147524,49.8125,-37.0477272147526));
#817=CARTESIAN_POINT('',(44.5477272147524,50.125,-37.0477272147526));
#818=CARTESIAN_POINT('',(44.5477272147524,50.28125,-37.0477272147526));
#819=CARTESIAN_POINT('',(44.5477272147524,50.59375,-37.0477272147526));
#820=CARTESIAN_POINT('',(44.5477272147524,50.75,-37.0477272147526));
#821=CARTESIAN_POINT('',(44.5477272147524,51.0625,-37.0477272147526));
#822=CARTESIAN_POINT('',(44.5477272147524,51.21875,-37.0477272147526));
#823=CARTESIAN_POINT('',(44.5477272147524,51.53125,-37.0477272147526));
#824=CARTESIAN_POINT('',(44.5477272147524,51.6875,-37.0477272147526));
#825=CARTESIAN_POINT('',(44.5477272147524,52.,-37.0477272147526));
#826=CARTESIAN_POINT('',(44.5477272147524,52.15625,-37.0477272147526));
#827=CARTESIAN_POINT('',(44.5477272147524,52.46875,-37.0477272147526));
#828=CARTESIAN_POINT('',(44.5477272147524,52.625,-37.0477272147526));
#829=CARTESIAN_POINT('',(44.5477272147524,52.9375,-37.0477272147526));
#830=CARTESIAN_POINT('',(44.5477272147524,53.09375,-37.0477272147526));
#831=CARTESIAN_POINT('',(44.5477272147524,53.40625,-37.0477272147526));
#832=CARTESIAN_POINT('',(44.5477272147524,53.5625,-37.0477272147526));
#833=CARTESIAN_POINT('',(44.5477272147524,53.875,-37.0477272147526));
#834=CARTESIAN_POINT('',(44.5477272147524,54.03125,-37.0477272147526));
#835=CARTESIAN_POINT('',(44.5477272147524,54.34375,-37.0477272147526));
#836=CARTESIAN_POINT('',(44.5477272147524,54.5,-37.0477272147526));
#837=CARTESIAN_POINT('',(44.5477272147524,54.8125,-37.0477272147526));
#838=CARTESIAN_POINT('',(44.5477272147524,54.96875,-37.0477272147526));
#839=CARTESIAN_POINT('',(44.5477272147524,55.28125,-37.0477272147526));
#840=CARTESIAN_POINT('',(44.5477272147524,55.4375,-37.0477272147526));
#841=CARTESIAN_POINT('',(44.5477272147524,55.75,-37.0477272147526));
#842=CARTESIAN_POINT('',(44.5477272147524,55.90625,-37.0477272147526));
#843=CARTESIAN_POINT('',(44.5477272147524,56.21875,-37.0477272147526));
#844=CARTESIAN_POINT('',(44.5477272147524,56.375,-37.0477272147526));
#845=CARTESIAN_POINT('',(44.5477272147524,56.6875,-37.0477272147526));
#846=CARTESIAN_POINT('',(44.5477272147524,56.84375,-37.0477272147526));
#847=CARTESIAN_POINT('',(44.5477272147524,57.,-37.0477272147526));
#848=B_SPLINE_CURVE_WITH_KNOTS('',3,(#782,#783,#784,#785,#786,#787,#788,#789,#790,#791,#792,
#793,#794,#795,#796,#797,#798,#799,#800,#801,#802,#803,#804,#805,#806,#807,#808,#809,#810,#811,
#812,#813,#814,#815,#816,#817,#818,#819,#820,#821,#822,#823,#824,#825,#826,#827,#828,#829,#830,
#831,#832,#833,#834,#835,#836,#837,#838,#839,#840,#841,#842,#843,#844,#845,#846,#847),
.UNSPECIFIED.,.F.,.F.,(4,2,2,2,2,2,2,2,2,2,2,2,2,2,2,2,2,2,2,2,2,2,2,2,2,2,2,2,2,2,2,2,4),(0.,
0.468749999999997,0.937500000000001,1.40625,1.875,2.34375,2.8125,3.28125,3.75,4.21875,4.6875,
5.15625,5.625,6.09375,6.5625,7.03125,7.5,7.96875,8.4375,8.90625,9.375,9.84375,10.3125,10.78125,
11.25,11.71875,12.1875,12.65625,13.125,13.59375,14.0625,14.53125,15.),.UNSPECIFIED.);
#849=EDGE_CURVE('BSEAM306',#242,#161,#848,.T.);
#850=ORIENTED_EDGE('',*,*,#243,.T.);
#851=ORIENTED_EDGE('',*,*,#162,.T.);
#852=ORIENTED_EDGE('',*,*,#849,.T.);
#853=ORIENTED_EDGE('',*,*,#849,.F.);
#854=EDGE_LOOP('',(#850,#852,#851,#853));
#855=FACE_BOUND('',#854,.T.);
#856=ADVANCED_FACE('F306',(#855),#781,.F.);
#857=CARTESIAN_POINT('',(-44.5477272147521,0.,-44.5477272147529));
#858=DIRECTION('',(0.,1.,0.));
#859=DIRECTION('',(0.,0.,1.));
#860=AXIS2_PLACEMENT_3D('',#857,#858,#859);
#861=CYLINDRICAL_SURFACE('',#860,7.5);
#862=CARTESIAN_POINT('',(-44.5477272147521,42.,-37.0477272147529));
#863=CARTESIAN_POINT('',(-44.5477272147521,42.15625,-37.0477272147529));
#864=CARTESIAN_POINT('',(-44.5477272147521,42.3125,-37.0477272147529));
#865=CARTESIAN_POINT('',(-44.5477272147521,42.625,-37.0477272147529));
#866=CARTESIAN_POINT('',(-44.5477272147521,42.78125,-37.0477272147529));
#867=CARTESIAN_POINT('',(-44.5477272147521,43.09375,-37.0477272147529));
#868=CARTESIAN_POINT('',(-44.5477272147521,43.25,-37.0477272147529));
#869=CARTESIAN_POINT('',(-44.5477272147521,43.5625,-37.0477272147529));
#870=CARTESIAN_POINT('',(-44.5477272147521,43.71875,-37.0477272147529));
#871=CARTESIAN_POINT('',(-44.5477272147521,44.03125,-37.0477272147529));
#872=CARTESIAN_POINT('',(-44.5477272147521,44.1875,-37.0477272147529));
#873=CARTESIAN_POINT('',(-44.5477272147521,44.5,-37.0477272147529));
#874=CARTESIAN_POINT('',(-44.5477272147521,44.65625,-37.0477272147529));
#875=CARTESIAN_POINT('',(-44.5477272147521,44.96875,-37.0477272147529));
#876=CARTESIAN_POINT('',(-44.5477272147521,45.125,-37.0477272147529));
#877=CARTESIAN_POINT('',(-44.5477272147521,45.4375,-37.0477272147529));
#878=CARTESIAN_POINT('',(-44.5477272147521,45.59375,-37.0477272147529));
#879=CARTESIAN_POINT('',(-44.5477272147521,45.90625,-37.0477272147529));
#880=CARTESIAN_POINT('',(-44.5477272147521,46.0625,-37.0477272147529));
#881=CARTESIAN_POINT('',(-44.5477272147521,46.375,-37.0477272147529));
#882=CARTESIAN_POINT('',(-44.5477272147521,46.53125,-37.0477272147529));
#883=CARTESIAN_POINT('',(-44.5477272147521,46.84375,-37.0477272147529));
#884=CARTESIAN_POINT('',(-44.5477272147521,47.,-37.0477272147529));
#885=CARTESIAN_POINT('',(-44.5477272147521,47.3125,-37.0477272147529));
#886=CARTESIAN_POINT('',(-44.5477272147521,47.46875,-37.0477272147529));
#887=CARTESIAN_POINT('',(-44.5477272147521,47.78125,-37.0477272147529));
#888=CARTESIAN_POINT('',(-44.5477272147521,47.9375,-37.0477272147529));
#889=CARTESIAN_POINT('',(-44.5477272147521,48.25,-37.0477272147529));
#890=CARTESIAN_POINT('',(-44.5477272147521,48.40625,-37.0477272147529));
#891=CARTESIAN_POINT('',(-44.5477272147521,48.71875,-37.0477272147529));
#892=CARTESIAN_POINT('',(-44.5477272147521,48.875,-37.0477272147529));
#893=CARTESIAN_POINT('',(-44.5477272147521,49.1875,-37.0477272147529));
#894=CARTESIAN_POINT('',(-44.5477272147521,49.34375,-37.0477272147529));
#895=CARTESIAN_POINT('',(-44.5477272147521,49.65625,-37.0477272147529));
#896=CARTESIAN_POINT('',(-44.5477272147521,49.8125,-37.0477272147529));
#897=CARTESIAN_POINT('',(-44.5477272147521,50.125,-37.0477272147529));
#898=CARTESIAN_POINT('',(-44.5477272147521,50.28125,-37.0477272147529));
#899=CARTESIAN_POINT('',(-44.5477272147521,50.59375,-37.0477272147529));
#900=CARTESIAN_POINT('',(-44.5477272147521,50.75,-37.0477272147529));
#901=CARTESIAN_POINT('',(-44.5477272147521,51.0625,-37.0477272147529));
#902=CARTESIAN_POINT('',(-44.5477272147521,51.21875,-37.0477272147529));
#903=CARTESIAN_POINT('',(-44.5477272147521,51.53125,-37.0477272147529));
#904=CARTESIAN_POINT('',(-44.5477272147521,51.6875,-37.0477272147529));
#905=CARTESIAN_POINT('',(-44.5477272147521,52.,-37.0477272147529));
#906=CARTESIAN_POINT('',(-44.5477272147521,52.15625,-37.0477272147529));
#907=CARTESIAN_POINT('',(-44.5477272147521,52.46875,-37.0477272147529));
#908=CARTESIAN_POINT('',(-44.5477272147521,52.625,-37.0477272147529));
#909=CARTESIAN_POINT('',(-44.5477272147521,52.9375,-37.0477272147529));
#910=CARTESIAN_POINT('',(-44.5477272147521,53.09375,-37.0477272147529));
#911=CARTESIAN_POINT('',(-44.5477272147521,53.40625,-37.0477272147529));
#912=CARTESIAN_POINT('',(-44.5477272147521,53.5625,-37.0477272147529));
#913=CARTESIAN_POINT('',(-44.5477272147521,53.875,-37.0477272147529));
#914=CARTESIAN_POINT('',(-44.5477272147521,54.03125,-37.0477272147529));
#915=CARTESIAN_POINT('',(-44.5477272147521,54.34375,-37.0477272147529));
#916=CARTESIAN_POINT('',(-44.5477272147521,54.5,-37.0477272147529));
#917=CARTESIAN_POINT('',(-44.5477272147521,54.8125,-37.0477272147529));
#918=CARTESIAN_POINT('',(-44.5477272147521,54.96875,-37.0477272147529));
#919=CARTESIAN_POINT('',(-44.5477272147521,55.28125,-37.0477272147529));
#920=CARTESIAN_POINT('',(-44.5477272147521,55.4375,-37.0477272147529));
#921=CARTESIAN_POINT('',(-44.5477272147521,55.75,-37.0477272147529));
#922=CARTESIAN_POINT('',(-44.5477272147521,55.90625,-37.0477272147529));
#923=CARTESIAN_POINT('',(-44.5477272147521,56.21875,-37.0477272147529));
#924=CARTESIAN_POINT('',(-44.5477272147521,56.375,-37.0477272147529));
#925=CARTESIAN_POINT('',(-44.5477272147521,56.6875,-37.0477272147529));
#926=CARTESIAN_POINT('',(-44.5477272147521,56.84375,-37.0477272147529));
#927=CARTESIAN_POINT('',(-44.5477272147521,57.,-37.0477272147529));
#928=B_SPLINE_CURVE_WITH_KNOTS('',3,(#862,#863,#864,#865,#866,#867,#868,#869,#870,#871,#872,
#873,#874,#875,#876,#877,#878,#879,#880,#881,#882,#883,#884,#885,#886,#887,#888,#889,#890,#891,
#892,#893,#894,#895,#896,#897,#898,#899,#900,#901,#902,#903,#904,#905,#906,#907,#908,#909,#910,
#911,#912,#913,#914,#915,#916,#917,#918,#919,#920,#921,#922,#923,#924,#925,#926,#927),
.UNSPECIFIED.,.F.,.F.,(4,2,2,2,2,2,2,2,2,2,2,2,2,2,2,2,2,2,2,2,2,2,2,2,2,2,2,2,2,2,2,2,4),(0.,
0.468749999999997,0.937500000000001,1.40625,1.875,2.34375,2.8125,3.28125,3.75,4.21875,4.6875,
5.15625,5.625,6.09375,6.5625,7.03125,7.5,7.96875,8.4375,8.90625,9.375,9.84375,10.3125,10.78125,
11.25,11.71875,12.1875,12.65625,13.125,13.59375,14.0625,14.53125,15.),.UNSPECIFIED.);
#929=EDGE_CURVE('BSEAM542',#231,#150,#928,.T.);
#930=ORIENTED_EDGE('',*,*,#232,.T.);
#931=ORIENTED_EDGE('',*,*,#151,.T.);
#932=ORIENTED_EDGE('',*,*,#929,.T.);
#933=ORIENTED_EDGE('',*,*,#929,.F.);
#934=EDGE_LOOP('',(#930,#932,#931,#933));
#935=FACE_BOUND('',#934,.T.);
#936=ADVANCED_FACE('F542',(#935),#861,.F.);
#937=CARTESIAN_POINT('',(-44.5477272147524,0.,44.5477272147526));
#938=DIRECTION('',(0.,1.,0.));
#939=DIRECTION('',(0.,0.,1.));
#940=AXIS2_PLACEMENT_3D('',#937,#938,#939);
#941=CYLINDRICAL_SURFACE('',#940,7.5);
#942=CARTESIAN_POINT('',(-44.5477272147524,42.,52.0477272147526));
#943=CARTESIAN_POINT('',(-44.5477272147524,42.15625,52.0477272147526));
#944=CARTESIAN_POINT('',(-44.5477272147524,42.3125,52.0477272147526));
#945=CARTESIAN_POINT('',(-44.5477272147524,42.625,52.0477272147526));
#946=CARTESIAN_POINT('',(-44.5477272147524,42.78125,52.0477272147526));
#947=CARTESIAN_POINT('',(-44.5477272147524,43.09375,52.0477272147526));
#948=CARTESIAN_POINT('',(-44.5477272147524,43.25,52.0477272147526));
#949=CARTESIAN_POINT('',(-44.5477272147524,43.5625,52.0477272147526));
#950=CARTESIAN_POINT('',(-44.5477272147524,43.71875,52.0477272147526));
#951=CARTESIAN_POINT('',(-44.5477272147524,44.03125,52.0477272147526));
#952=CARTESIAN_POINT('',(-44.5477272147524,44.1875,52.0477272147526));
#953=CARTESIAN_POINT('',(-44.5477272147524,44.5,52.0477272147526));
#954=CARTESIAN_POINT('',(-44.5477272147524,44.65625,52.0477272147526));
#955=CARTESIAN_POINT('',(-44.5477272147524,44.96875,52.0477272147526));
#956=CARTESIAN_POINT('',(-44.5477272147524,45.125,52.0477272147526));
#957=CARTESIAN_POINT('',(-44.5477272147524,45.4375,52.0477272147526));
#958=CARTESIAN_POINT('',(-44.5477272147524,45.59375,52.0477272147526));
#959=CARTESIAN_POINT('',(-44.5477272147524,45.90625,52.0477272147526));
#960=CARTESIAN_POINT('',(-44.5477272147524,46.0625,52.0477272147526));
#961=CARTESIAN_POINT('',(-44.5477272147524,46.375,52.0477272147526));
#962=CARTESIAN_POINT('',(-44.5477272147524,46.53125,52.0477272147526));
#963=CARTESIAN_POINT('',(-44.5477272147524,46.84375,52.0477272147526));
#964=CARTESIAN_POINT('',(-44.5477272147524,47.,52.0477272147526));
#965=CARTESIAN_POINT('',(-44.5477272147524,47.3125,52.0477272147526));
#966=CARTESIAN_POINT('',(-44.5477272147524,47.46875,52.0477272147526));
#967=CARTESIAN_POINT('',(-44.5477272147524,47.78125,52.0477272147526));
#968=CARTESIAN_POINT('',(-44.5477272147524,47.9375,52.0477272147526));
#969=CARTESIAN_POINT('',(-44.5477272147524,48.25,52.0477272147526));
#970=CARTESIAN_POINT('',(-44.5477272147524,48.40625,52.0477272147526));
#971=CARTESIAN_POINT('',(-44.5477272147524,48.71875,52.0477272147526));
#972=CARTESIAN_POINT('',(-44.5477272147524,48.875,52.0477272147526));
#973=CARTESIAN_POINT('',(-44.5477272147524,49.1875,52.0477272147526));
#974=CARTESIAN_POINT('',(-44.5477272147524,49.34375,52.0477272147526));
#975=CARTESIAN_POINT('',(-44.5477272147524,49.65625,52.0477272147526));
#976=CARTESIAN_POINT('',(-44.5477272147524,49.8125,52.0477272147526));
#977=CARTESIAN_POINT('',(-44.5477272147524,50.125,52.0477272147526));
#978=CARTESIAN_POINT('',(-44.5477272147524,50.28125,52.0477272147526));
#979=CARTESIAN_POINT('',(-44.5477272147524,50.59375,52.0477272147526));
#980=CARTESIAN_POINT('',(-44.5477272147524,50.75,52.0477272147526));
#981=CARTESIAN_POINT('',(-44.5477272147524,51.0625,52.0477272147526));
#982=CARTESIAN_POINT('',(-44.5477272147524,51.21875,52.0477272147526));
#983=CARTESIAN_POINT('',(-44.5477272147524,51.53125,52.0477272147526));
#984=CARTESIAN_POINT('',(-44.5477272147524,51.6875,52.0477272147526));
#985=CARTESIAN_POINT('',(-44.5477272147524,52.,52.0477272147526));
#986=CARTESIAN_POINT('',(-44.5477272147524,52.15625,52.0477272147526));
#987=CARTESIAN_POINT('',(-44.5477272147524,52.46875,52.0477272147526));
#988=CARTESIAN_POINT('',(-44.5477272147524,52.625,52.0477272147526));
#989=CARTESIAN_POINT('',(-44.5477272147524,52.9375,52.0477272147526));
#990=CARTESIAN_POINT('',(-44.5477272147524,53.09375,52.0477272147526));
#991=CARTESIAN_POINT('',(-44.5477272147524,53.40625,52.0477272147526));
#992=CARTESIAN_POINT('',(-44.5477272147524,53.5625,52.0477272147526));
#993=CARTESIAN_POINT('',(-44.5477272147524,53.875,52.0477272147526));
#994=CARTESIAN_POINT('',(-44.5477272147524,54.03125,52.0477272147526));
#995=CARTESIAN_POINT('',(-44.5477272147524,54.34375,52.0477272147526));
#996=CARTESIAN_POINT('',(-44.5477272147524,54.5,52.0477272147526));
#997=CARTESIAN_POINT('',(-44.5477272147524,54.8125,52.0477272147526));
#998=CARTESIAN_POINT('',(-44.5477272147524,54.96875,52.0477272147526));
#999=CARTESIAN_POINT('',(-44.5477272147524,55.28125,52.0477272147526));
#1000=CARTESIAN_POINT('',(-44.5477272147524,55.4375,52.0477272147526));
#1001=CARTESIAN_POINT('',(-44.5477272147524,55.75,52.0477272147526));
#1002=CARTESIAN_POINT('',(-44.5477272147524,55.90625,52.0477272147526));
#1003=CARTESIAN_POINT('',(-44.5477272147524,56.21875,52.0477272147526));
#1004=CARTESIAN_POINT('',(-44.5477272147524,56.375,52.0477272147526));
#1005=CARTESIAN_POINT('',(-44.5477272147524,56.6875,52.0477272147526));
#1006=CARTESIAN_POINT('',(-44.5477272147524,56.84375,52.0477272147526));
#1007=CARTESIAN_POINT('',(-44.5477272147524,57.,52.0477272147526));
#1008=B_SPLINE_CURVE_WITH_KNOTS('',3,(#942,#943,#944,#945,#946,#947,#948,#949,#950,#951,#952,
#953,#954,#955,#956,#957,#958,#959,#960,#961,#962,#963,#964,#965,#966,#967,#968,#969,#970,#971,
#972,#973,#974,#975,#976,#977,#978,#979,#980,#981,#982,#983,#984,#985,#986,#987,#988,#989,#990,
#991,#992,#993,#994,#995,#996,#997,#998,#999,#1000,#1001,#1002,#1003,#1004,#1005,#1006,#1007),
.UNSPECIFIED.,.F.,.F.,(4,2,2,2,2,2,2,2,2,2,2,2,2,2,2,2,2,2,2,2,2,2,2,2,2,2,2,2,2,2,2,2,4),(0.,
0.468749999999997,0.937500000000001,1.40625,1.875,2.34375,2.8125,3.28125,3.75,4.21875,4.6875,
5.15625,5.625,6.09375,6.5625,7.03125,7.5,7.96875,8.4375,8.90625,9.375,9.84375,10.3125,10.78125,
11.25,11.71875,12.1875,12.65625,13.125,13.59375,14.0625,14.53125,15.),.UNSPECIFIED.);
#1009=EDGE_CURVE('BSEAM374',#220,#139,#1008,.T.);
#1010=ORIENTED_EDGE('',*,*,#221,.T.);
#1011=ORIENTED_EDGE('',*,*,#140,.T.);
#1012=ORIENTED_EDGE('',*,*,#1009,.T.);
#1013=ORIENTED_EDGE('',*,*,#1009,.F.);
#1014=EDGE_LOOP('',(#1010,#1012,#1011,#1013));
#1015=FACE_BOUND('',#1014,.T.);
#1016=ADVANCED_FACE('F374',(#1015),#941,.F.);
#1017=CARTESIAN_POINT('',(44.5477272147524,0.,44.5477272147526));
#1018=DIRECTION('',(0.,1.,0.));
#1019=DIRECTION('',(0.,0.,1.));
#1020=AXIS2_PLACEMENT_3D('',#1017,#1018,#1019);
#1021=CYLINDRICAL_SURFACE('',#1020,7.5);
#1022=CARTESIAN_POINT('',(44.5477272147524,42.,52.0477272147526));
#1023=CARTESIAN_POINT('',(44.5477272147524,42.15625,52.0477272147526));
#1024=CARTESIAN_POINT('',(44.5477272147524,42.3125,52.0477272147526));
#1025=CARTESIAN_POINT('',(44.5477272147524,42.625,52.0477272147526));
#1026=CARTESIAN_POINT('',(44.5477272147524,42.78125,52.0477272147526));
#1027=CARTESIAN_POINT('',(44.5477272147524,43.09375,52.0477272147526));
#1028=CARTESIAN_POINT('',(44.5477272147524,43.25,52.0477272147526));
#1029=CARTESIAN_POINT('',(44.5477272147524,43.5625,52.0477272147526));
#1030=CARTESIAN_POINT('',(44.5477272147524,43.71875,52.0477272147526));
#1031=CARTESIAN_POINT('',(44.5477272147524,44.03125,52.0477272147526));
#1032=CARTESIAN_POINT('',(44.5477272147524,44.1875,52.0477272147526));
#1033=CARTESIAN_POINT('',(44.5477272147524,44.5,52.0477272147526));
#1034=CARTESIAN_POINT('',(44.5477272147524,44.65625,52.0477272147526));
#1035=CARTESIAN_POINT('',(44.5477272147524,44.96875,52.0477272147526));
#1036=CARTESIAN_POINT('',(44.5477272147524,45.125,52.0477272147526));
#1037=CARTESIAN_POINT('',(44.5477272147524,45.4375,52.0477272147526));
#1038=CARTESIAN_POINT('',(44.5477272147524,45.59375,52.0477272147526));
#1039=CARTESIAN_POINT('',(44.5477272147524,45.90625,52.0477272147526));
#1040=CARTESIAN_POINT('',(44.5477272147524,46.0625,52.0477272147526));
#1041=CARTESIAN_POINT('',(44.5477272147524,46.375,52.0477272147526));
#1042=CARTESIAN_POINT('',(44.5477272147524,46.53125,52.0477272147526));
#1043=CARTESIAN_POINT('',(44.5477272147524,46.84375,52.0477272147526));
#1044=CARTESIAN_POINT('',(44.5477272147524,47.,52.0477272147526));
#1045=CARTESIAN_POINT('',(44.5477272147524,47.3125,52.0477272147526));
#1046=CARTESIAN_POINT('',(44.5477272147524,47.46875,52.0477272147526));
#1047=CARTESIAN_POINT('',(44.5477272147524,47.78125,52.0477272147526));
#1048=CARTESIAN_POINT('',(44.5477272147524,47.9375,52.0477272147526));
#1049=CARTESIAN_POINT('',(44.5477272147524,48.25,52.0477272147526));
#1050=CARTESIAN_POINT('',(44.5477272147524,48.40625,52.0477272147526));
#1051=CARTESIAN_POINT('',(44.5477272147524,48.71875,52.0477272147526));
#1052=CARTESIAN_POINT('',(44.5477272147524,48.875,52.0477272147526));
#1053=CARTESIAN_POINT('',(44.5477272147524,49.1875,52.0477272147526));
#1054=CARTESIAN_POINT('',(44.5477272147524,49.34375,52.0477272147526));
#1055=CARTESIAN_POINT('',(44.5477272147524,49.65625,52.0477272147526));
#1056=CARTESIAN_POINT('',(44.5477272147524,49.8125,52.0477272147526));
#1057=CARTESIAN_POINT('',(44.5477272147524,50.125,52.0477272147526));
#1058=CARTESIAN_POINT('',(44.5477272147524,50.28125,52.0477272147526));
#1059=CARTESIAN_POINT('',(44.5477272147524,50.59375,52.0477272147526));
#1060=CARTESIAN_POINT('',(44.5477272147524,50.75,52.0477272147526));
#1061=CARTESIAN_POINT('',(44.5477272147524,51.0625,52.0477272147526));
#1062=CARTESIAN_POINT('',(44.5477272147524,51.21875,52.0477272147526));
#1063=CARTESIAN_POINT('',(44.5477272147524,51.53125,52.0477272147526));
#1064=CARTESIAN_POINT('',(44.5477272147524,51.6875,52.0477272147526));
#1065=CARTESIAN_POINT('',(44.5477272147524,52.,52.0477272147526));
#1066=CARTESIAN_POINT('',(44.5477272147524,52.15625,52.0477272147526));
#1067=CARTESIAN_POINT('',(44.5477272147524,52.46875,52.0477272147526));
#1068=CARTESIAN_POINT('',(44.5477272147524,52.625,52.0477272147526));
#1069=CARTESIAN_POINT('',(44.5477272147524,52.9375,52.0477272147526));
#1070=CARTESIAN_POINT('',(44.5477272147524,53.09375,52.0477272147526));
#1071=CARTESIAN_POINT('',(44.5477272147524,53.40625,52.0477272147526));
#1072=CARTESIAN_POINT('',(44.5477272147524,53.5625,52.0477272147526));
#1073=CARTESIAN_POINT('',(44.5477272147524,53.875,52.0477272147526));
#1074=CARTESIAN_POINT('',(44.5477272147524,54.03125,52.0477272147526));
#1075=CARTESIAN_POINT('',(44.5477272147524,54.34375,52.0477272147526));
#1076=CARTESIAN_POINT('',(44.5477272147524,54.5,52.0477272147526));
#1077=CARTESIAN_POINT('',(44.5477272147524,54.8125,52.0477272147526));
#1078=CARTESIAN_POINT('',(44.5477272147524,54.96875,52.0477272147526));
#1079=CARTESIAN_POINT('',(44.5477272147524,55.28125,52.0477272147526));
#1080=CARTESIAN_POINT('',(44.5477272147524,55.4375,52.0477272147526));
#1081=CARTESIAN_POINT('',(44.5477272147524,55.75,52.0477272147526));
#1082=CARTESIAN_POINT('',(44.5477272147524,55.90625,52.0477272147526));
#1083=CARTESIAN_POINT('',(44.5477272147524,56.21875,52.0477272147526));
#1084=CARTESIAN_POINT('',(44.5477272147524,56.375,52.0477272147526));
#1085=CARTESIAN_POINT('',(44.5477272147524,56.6875,52.0477272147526));
#1086=CARTESIAN_POINT('',(44.5477272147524,56.84375,52.0477272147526));
#1087=CARTESIAN_POINT('',(44.5477272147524,57.,52.0477272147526));
#1088=B_SPLINE_CURVE_WITH_KNOTS('',3,(#1022,#1023,#1024,#1025,#1026,#1027,#1028,#1029,#1030,
#1031,#1032,#1033,#1034,#1035,#1036,#1037,#1038,#1039,#1040,#1041,#1042,#1043,#1044,#1045,#1046,
#1047,#1048,#1049,#1050,#1051,#1052,#1053,#1054,#1055,#1056,#1057,#1058,#1059,#1060,#1061,#1062,
#1063,#1064,#1065,#1066,#1067,#1068,#1069,#1070,#1071,#1072,#1073,#1074,#1075,#1076,#1077,#1078,
#1079,#1080,#1081,#1082,#1083,#1084,#1085,#1086,#1087),.UNSPECIFIED.,.F.,.F.,(4,2,2,2,2,2,2,2,2,
2,2,2,2,2,2,2,2,2,2,2,2,2,2,2,2,2,2,2,2,2,2,2,4),(0.,0.468749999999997,0.937500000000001,
1.40625,1.875,2.34375,2.8125,3.28125,3.75,4.21875,4.6875,5.15625,5.625,6.09375,6.5625,7.03125,
7.5,7.96875,8.4375,8.90625,9.375,9.84375,10.3125,10.78125,11.25,11.71875,12.1875,12.65625,
13.125,13.59375,14.0625,14.53125,15.),.UNSPECIFIED.);
#1089=EDGE_CURVE('BSEAM369',#209,#128,#1088,.T.);
#1090=ORIENTED_EDGE('',*,*,#210,.T.);
#1091=ORIENTED_EDGE('',*,*,#129,.T.);
#1092=ORIENTED_EDGE('',*,*,#1089,.T.);
#1093=ORIENTED_EDGE('',*,*,#1089,.F.);
#1094=EDGE_LOOP('',(#1090,#1092,#1091,#1093));
#1095=FACE_BOUND('',#1094,.T.);
#1096=ADVANCED_FACE('F369',(#1095),#1021,.F.);
#1097=CARTESIAN_POINT('',(14.4,62.,-32.9945450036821));
#1098=DIRECTION('',(-0.916515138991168,0.,-0.4));
#1099=DIRECTION('',(-0.4,0.,0.916515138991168));
#1100=AXIS2_PLACEMENT_3D('',#1097,#1098,#1099);
#1101=CYLINDRICAL_SURFACE('',#1100,5.);
#1102=CARTESIAN_POINT('',(45.9,62.,-19.2468179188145));
#1103=DIRECTION('',(-0.916515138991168,0.,-0.400000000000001));
#1104=DIRECTION('',(-0.400000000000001,0.,0.916515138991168));
#1105=AXIS2_PLACEMENT_3D('',#1102,#1103,#1104);
#1106=CIRCLE('',#1105,5.);
#1107=EDGE_CURVE('E283',#102,#423,#1106,.T.);
#1108=ORIENTED_EDGE('',*,*,#1107,.F.);
#1109=ORIENTED_EDGE('',*,*,#103,.F.);
#1110=CARTESIAN_POINT('',(14.4,62.,-32.9945450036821));
#1111=DIRECTION('',(0.916515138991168,0.,0.4));
#1112=DIRECTION('',(0.4,0.,-0.916515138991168));
#1113=AXIS2_PLACEMENT_3D('',#1110,#1111,#1112);
#1114=CIRCLE('',#1113,5.);
#1115=EDGE_CURVE('E36',#455,#94,#1114,.T.);
#1116=ORIENTED_EDGE('',*,*,#1115,.F.);
#1117=ORIENTED_EDGE('',*,*,#456,.F.);
#1118=EDGE_LOOP('',(#1108,#1109,#1116,#1117));
#1119=FACE_BOUND('',#1118,.T.);
#1120=ADVANCED_FACE('F34',(#1119),#1101,.F.);
#1121=CARTESIAN_POINT('',(0.,62.,0.));
#1122=DIRECTION('',(0.,1.,0.));
#1123=DIRECTION('',(0.,0.,1.));
#1124=AXIS2_PLACEMENT_3D('',#1121,#1122,#1123);
#1125=TOROIDAL_SURFACE('',#1124,36.,5.);
#1126=ORIENTED_EDGE('',*,*,#1115,.T.);
#1127=ORIENTED_EDGE('',*,*,#95,.F.);
#1128=CARTESIAN_POINT('',(-14.4,62.,-32.9945450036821));
#1129=DIRECTION('',(0.916515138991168,0.,-0.4));
#1130=DIRECTION('',(-0.4,0.,-0.916515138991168));
#1131=AXIS2_PLACEMENT_3D('',#1128,#1129,#1130);
#1132=CIRCLE('',#1131,5.);
#1133=EDGE_CURVE('E281',#487,#85,#1132,.T.);
#1134=ORIENTED_EDGE('',*,*,#1133,.F.);
#1135=ORIENTED_EDGE('',*,*,#488,.F.);
#1136=EDGE_LOOP('',(#1126,#1127,#1134,#1135));
#1137=FACE_BOUND('',#1136,.T.);
#1138=ADVANCED_FACE('F364',(#1137),#1125,.F.);
#1139=CARTESIAN_POINT('',(37.5,62.,0.));
#1140=DIRECTION('',(0.,1.,0.));
#1141=DIRECTION('',(0.,0.,1.));
#1142=AXIS2_PLACEMENT_3D('',#1139,#1140,#1141);
#1143=TOROIDAL_SURFACE('',#1142,21.,5.);
#1144=ORIENTED_EDGE('',*,*,#1107,.T.);
#1145=ORIENTED_EDGE('',*,*,#424,.F.);
#1146=CARTESIAN_POINT('',(45.9,62.,19.2468179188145));
#1147=DIRECTION('',(0.916515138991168,0.,-0.4));
#1148=DIRECTION('',(-0.4,0.,-0.916515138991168));
#1149=AXIS2_PLACEMENT_3D('',#1146,#1147,#1148);
#1150=CIRCLE('',#1149,5.);
#1151=EDGE_CURVE('E278',#111,#391,#1150,.T.);
#1152=ORIENTED_EDGE('',*,*,#1151,.F.);
#1153=ORIENTED_EDGE('',*,*,#112,.F.);
#1154=EDGE_LOOP('',(#1144,#1145,#1152,#1153));
#1155=FACE_BOUND('',#1154,.T.);
#1156=ADVANCED_FACE('F361',(#1155),#1143,.F.);
#1157=CARTESIAN_POINT('',(-45.9,62.,-19.2468179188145));
#1158=DIRECTION('',(-0.916515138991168,0.,0.4));
#1159=DIRECTION('',(0.4,0.,0.916515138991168));
#1160=AXIS2_PLACEMENT_3D('',#1157,#1158,#1159);
#1161=CYLINDRICAL_SURFACE('',#1160,5.);
#1162=ORIENTED_EDGE('',*,*,#1133,.T.);
#1163=ORIENTED_EDGE('',*,*,#86,.F.);
#1164=CARTESIAN_POINT('',(-45.9,62.,-19.2468179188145));
#1165=DIRECTION('',(0.916515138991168,0.,-0.4));
#1166=DIRECTION('',(-0.4,0.,-0.916515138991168));
#1167=AXIS2_PLACEMENT_3D('',#1164,#1165,#1166);
#1168=CIRCLE('',#1167,5.);
#1169=EDGE_CURVE('E275',#286,#77,#1168,.T.);
#1170=ORIENTED_EDGE('',*,*,#1169,.F.);
#1171=ORIENTED_EDGE('',*,*,#518,.F.);
#1172=EDGE_LOOP('',(#1162,#1163,#1170,#1171));
#1173=FACE_BOUND('',#1172,.T.);
#1174=ADVANCED_FACE('F357',(#1173),#1161,.F.);
#1175=CARTESIAN_POINT('',(14.4,62.,32.994545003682));
#1176=DIRECTION('',(0.916515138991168,0.,-0.4));
#1177=DIRECTION('',(-0.4,0.,-0.916515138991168));
#1178=AXIS2_PLACEMENT_3D('',#1175,#1176,#1177);
#1179=CYLINDRICAL_SURFACE('',#1178,5.);
#1180=ORIENTED_EDGE('',*,*,#1151,.T.);
#1181=ORIENTED_EDGE('',*,*,#392,.F.);
#1182=CARTESIAN_POINT('',(14.4,62.,32.994545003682));
#1183=DIRECTION('',(0.916515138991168,0.,-0.4));
#1184=DIRECTION('',(-0.400000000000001,0.,-0.916515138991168));
#1185=AXIS2_PLACEMENT_3D('',#1182,#1183,#1184);
#1186=CIRCLE('',#1185,5.);
#1187=EDGE_CURVE('E272',#58,#359,#1186,.T.);
#1188=ORIENTED_EDGE('',*,*,#1187,.F.);
#1189=ORIENTED_EDGE('',*,*,#118,.F.);
#1190=EDGE_LOOP('',(#1180,#1181,#1188,#1189));
#1191=FACE_BOUND('',#1190,.T.);
#1192=ADVANCED_FACE('F353',(#1191),#1179,.F.);
#1193=CARTESIAN_POINT('',(-37.5,62.,0.));
#1194=DIRECTION('',(0.,1.,0.));
#1195=DIRECTION('',(0.,0.,1.));
#1196=AXIS2_PLACEMENT_3D('',#1193,#1194,#1195);
#1197=TOROIDAL_SURFACE('',#1196,21.,5.);
#1198=ORIENTED_EDGE('',*,*,#1169,.T.);
#1199=ORIENTED_EDGE('',*,*,#78,.F.);
#1200=CARTESIAN_POINT('',(-45.9,62.,19.2468179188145));
#1201=DIRECTION('',(-0.916515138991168,0.,-0.4));
#1202=DIRECTION('',(-0.4,0.,0.916515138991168));
#1203=AXIS2_PLACEMENT_3D('',#1200,#1201,#1202);
#1204=CIRCLE('',#1203,5.);
#1205=EDGE_CURVE('E270',#295,#68,#1204,.T.);
#1206=ORIENTED_EDGE('',*,*,#1205,.F.);
#1207=ORIENTED_EDGE('',*,*,#296,.F.);
#1208=EDGE_LOOP('',(#1198,#1199,#1206,#1207));
#1209=FACE_BOUND('',#1208,.T.);
#1210=ADVANCED_FACE('F349',(#1209),#1197,.F.);
#1211=CARTESIAN_POINT('',(0.,62.,0.));
#1212=DIRECTION('',(0.,1.,0.));
#1213=DIRECTION('',(0.,0.,1.));
#1214=AXIS2_PLACEMENT_3D('',#1211,#1212,#1213);
#1215=TOROIDAL_SURFACE('',#1214,36.,5.);
#1216=ORIENTED_EDGE('',*,*,#1187,.T.);
#1217=ORIENTED_EDGE('',*,*,#360,.F.);
#1218=CARTESIAN_POINT('',(-14.4,62.,32.994545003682));
#1219=DIRECTION('',(0.916515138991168,0.,0.4));
#1220=DIRECTION('',(0.4,0.,-0.916515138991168));
#1221=AXIS2_PLACEMENT_3D('',#1218,#1219,#1220);
#1222=CIRCLE('',#1221,5.);
#1223=EDGE_CURVE('E268',#60,#327,#1222,.T.);
#1224=ORIENTED_EDGE('',*,*,#1223,.F.);
#1225=ORIENTED_EDGE('',*,*,#61,.F.);
#1226=EDGE_LOOP('',(#1216,#1217,#1224,#1225));
#1227=FACE_BOUND('',#1226,.T.);
#1228=ADVANCED_FACE('F345',(#1227),#1215,.F.);
#1229=CARTESIAN_POINT('',(-45.9,62.,19.2468179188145));
#1230=DIRECTION('',(0.916515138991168,0.,0.4));
#1231=DIRECTION('',(0.4,0.,-0.916515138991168));
#1232=AXIS2_PLACEMENT_3D('',#1229,#1230,#1231);
#1233=CYLINDRICAL_SURFACE('',#1232,5.);
#1234=ORIENTED_EDGE('',*,*,#1205,.T.);
#1235=ORIENTED_EDGE('',*,*,#69,.F.);
#1236=ORIENTED_EDGE('',*,*,#1223,.T.);
#1237=ORIENTED_EDGE('',*,*,#328,.F.);
#1238=EDGE_LOOP('',(#1234,#1235,#1236,#1237));
#1239=FACE_BOUND('',#1238,.T.);
#1240=ADVANCED_FACE('F342',(#1239),#1233,.F.);
#1241=CLOSED_SHELL('',(#46,#177,#197,#261,#273,#315,#346,#379,#410,#443,#474,#507,#529,#578,
#598,#618,#638,#658,#678,#698,#710,#731,#743,#764,#776,#856,#936,#1016,#1096,#1120,#1138,#1156,
#1174,#1192,#1210,#1228,#1240));
#1242=MANIFOLD_SOLID_BREP('B2',#1241);
#1243=ADVANCED_BREP_SHAPE_REPRESENTATION('',(#18,#1242),#14);
#1244=SHAPE_DEFINITION_REPRESENTATION(#9,#1243);
ENDSEC;
END-ISO-10303-21;
